VERSION 5.8 ;
BUSBITCHARS "[]" ;
DIVIDERCHAR "/" ;
UNITS
    DATABASE MICRONS 1000 ;
END UNITS

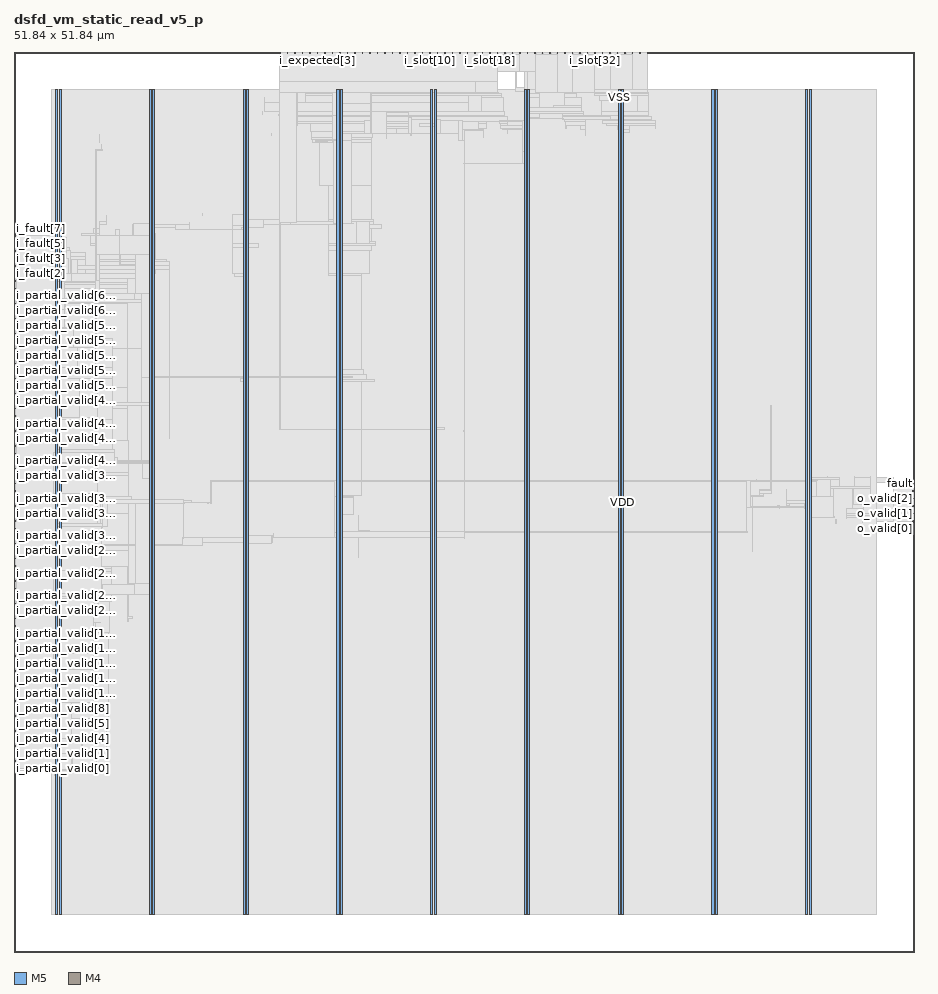
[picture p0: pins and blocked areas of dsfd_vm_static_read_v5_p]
MACRO dsfd_vm_static_read_v5_p
  FOREIGN dsfd_vm_static_read_v5_p 0 0 ;
  CLASS BLOCK ;
  SIZE 51.84 BY 51.84 ;
  PIN ck
    DIRECTION INPUT ;
    USE SIGNAL ;
    PORT
      LAYER M5 ;
        RECT  15.312 51.756 15.336 51.84 ;
    END
  END ck
  PIN fault
    DIRECTION OUTPUT ;
    USE SIGNAL ;
    PORT
      LAYER M4 ;
        RECT  51.756 26.976 51.84 27 ;
    END
  END fault
  PIN i_expected[0]
    DIRECTION INPUT ;
    USE SIGNAL ;
    PORT
      LAYER M5 ;
        RECT  16.176 51.756 16.2 51.84 ;
    END
  END i_expected[0]
  PIN i_expected[1]
    DIRECTION INPUT ;
    USE SIGNAL ;
    PORT
      LAYER M5 ;
        RECT  16.608 51.756 16.632 51.84 ;
    END
  END i_expected[1]
  PIN i_expected[2]
    DIRECTION INPUT ;
    USE SIGNAL ;
    PORT
      LAYER M5 ;
        RECT  17.04 51.756 17.064 51.84 ;
    END
  END i_expected[2]
  PIN i_expected[3]
    DIRECTION INPUT ;
    USE SIGNAL ;
    PORT
      LAYER M5 ;
        RECT  17.472 51.756 17.496 51.84 ;
    END
  END i_expected[3]
  PIN i_expected[4]
    DIRECTION INPUT ;
    USE SIGNAL ;
    PORT
      LAYER M5 ;
        RECT  17.904 51.756 17.928 51.84 ;
    END
  END i_expected[4]
  PIN i_expected[5]
    DIRECTION INPUT ;
    USE SIGNAL ;
    PORT
      LAYER M5 ;
        RECT  18.336 51.756 18.36 51.84 ;
    END
  END i_expected[5]
  PIN i_expected[6]
    DIRECTION INPUT ;
    USE SIGNAL ;
    PORT
      LAYER M5 ;
        RECT  18.768 51.756 18.792 51.84 ;
    END
  END i_expected[6]
  PIN i_expected[7]
    DIRECTION INPUT ;
    USE SIGNAL ;
    PORT
      LAYER M5 ;
        RECT  19.2 51.756 19.224 51.84 ;
    END
  END i_expected[7]
  PIN i_fault[0]
    DIRECTION INPUT ;
    USE SIGNAL ;
    PORT
      LAYER M4 ;
        RECT  0 38.208 0.084 38.232 ;
    END
  END i_fault[0]
  PIN i_fault[1]
    DIRECTION INPUT ;
    USE SIGNAL ;
    PORT
      LAYER M4 ;
        RECT  0 38.64 0.084 38.664 ;
    END
  END i_fault[1]
  PIN i_fault[2]
    DIRECTION INPUT ;
    USE SIGNAL ;
    PORT
      LAYER M4 ;
        RECT  0 39.072 0.084 39.096 ;
    END
  END i_fault[2]
  PIN i_fault[3]
    DIRECTION INPUT ;
    USE SIGNAL ;
    PORT
      LAYER M4 ;
        RECT  0 39.504 0.084 39.528 ;
    END
  END i_fault[3]
  PIN i_fault[4]
    DIRECTION INPUT ;
    USE SIGNAL ;
    PORT
      LAYER M4 ;
        RECT  0 39.936 0.084 39.96 ;
    END
  END i_fault[4]
  PIN i_fault[5]
    DIRECTION INPUT ;
    USE SIGNAL ;
    PORT
      LAYER M4 ;
        RECT  0 40.368 0.084 40.392 ;
    END
  END i_fault[5]
  PIN i_fault[6]
    DIRECTION INPUT ;
    USE SIGNAL ;
    PORT
      LAYER M4 ;
        RECT  0 40.8 0.084 40.824 ;
    END
  END i_fault[6]
  PIN i_fault[7]
    DIRECTION INPUT ;
    USE SIGNAL ;
    PORT
      LAYER M4 ;
        RECT  0 41.232 0.084 41.256 ;
    END
  END i_fault[7]
  PIN i_partial_valid[0]
    DIRECTION INPUT ;
    USE SIGNAL ;
    PORT
      LAYER M4 ;
        RECT  0 10.56 0.084 10.584 ;
    END
  END i_partial_valid[0]
  PIN i_partial_valid[10]
    DIRECTION INPUT ;
    USE SIGNAL ;
    PORT
      LAYER M4 ;
        RECT  0 14.88 0.084 14.904 ;
    END
  END i_partial_valid[10]
  PIN i_partial_valid[11]
    DIRECTION INPUT ;
    USE SIGNAL ;
    PORT
      LAYER M4 ;
        RECT  0 15.312 0.084 15.336 ;
    END
  END i_partial_valid[11]
  PIN i_partial_valid[12]
    DIRECTION INPUT ;
    USE SIGNAL ;
    PORT
      LAYER M4 ;
        RECT  0 15.744 0.084 15.768 ;
    END
  END i_partial_valid[12]
  PIN i_partial_valid[13]
    DIRECTION INPUT ;
    USE SIGNAL ;
    PORT
      LAYER M4 ;
        RECT  0 16.176 0.084 16.2 ;
    END
  END i_partial_valid[13]
  PIN i_partial_valid[14]
    DIRECTION INPUT ;
    USE SIGNAL ;
    PORT
      LAYER M4 ;
        RECT  0 16.608 0.084 16.632 ;
    END
  END i_partial_valid[14]
  PIN i_partial_valid[15]
    DIRECTION INPUT ;
    USE SIGNAL ;
    PORT
      LAYER M4 ;
        RECT  0 17.04 0.084 17.064 ;
    END
  END i_partial_valid[15]
  PIN i_partial_valid[16]
    DIRECTION INPUT ;
    USE SIGNAL ;
    PORT
      LAYER M4 ;
        RECT  0 17.472 0.084 17.496 ;
    END
  END i_partial_valid[16]
  PIN i_partial_valid[17]
    DIRECTION INPUT ;
    USE SIGNAL ;
    PORT
      LAYER M4 ;
        RECT  0 17.904 0.084 17.928 ;
    END
  END i_partial_valid[17]
  PIN i_partial_valid[18]
    DIRECTION INPUT ;
    USE SIGNAL ;
    PORT
      LAYER M4 ;
        RECT  0 18.336 0.084 18.36 ;
    END
  END i_partial_valid[18]
  PIN i_partial_valid[19]
    DIRECTION INPUT ;
    USE SIGNAL ;
    PORT
      LAYER M4 ;
        RECT  0 18.768 0.084 18.792 ;
    END
  END i_partial_valid[19]
  PIN i_partial_valid[1]
    DIRECTION INPUT ;
    USE SIGNAL ;
    PORT
      LAYER M4 ;
        RECT  0 10.992 0.084 11.016 ;
    END
  END i_partial_valid[1]
  PIN i_partial_valid[20]
    DIRECTION INPUT ;
    USE SIGNAL ;
    PORT
      LAYER M4 ;
        RECT  0 19.2 0.084 19.224 ;
    END
  END i_partial_valid[20]
  PIN i_partial_valid[21]
    DIRECTION INPUT ;
    USE SIGNAL ;
    PORT
      LAYER M4 ;
        RECT  0 19.632 0.084 19.656 ;
    END
  END i_partial_valid[21]
  PIN i_partial_valid[22]
    DIRECTION INPUT ;
    USE SIGNAL ;
    PORT
      LAYER M4 ;
        RECT  0 20.064 0.084 20.088 ;
    END
  END i_partial_valid[22]
  PIN i_partial_valid[23]
    DIRECTION INPUT ;
    USE SIGNAL ;
    PORT
      LAYER M4 ;
        RECT  0 20.496 0.084 20.52 ;
    END
  END i_partial_valid[23]
  PIN i_partial_valid[24]
    DIRECTION INPUT ;
    USE SIGNAL ;
    PORT
      LAYER M4 ;
        RECT  0 20.928 0.084 20.952 ;
    END
  END i_partial_valid[24]
  PIN i_partial_valid[25]
    DIRECTION INPUT ;
    USE SIGNAL ;
    PORT
      LAYER M4 ;
        RECT  0 21.36 0.084 21.384 ;
    END
  END i_partial_valid[25]
  PIN i_partial_valid[26]
    DIRECTION INPUT ;
    USE SIGNAL ;
    PORT
      LAYER M4 ;
        RECT  0 21.792 0.084 21.816 ;
    END
  END i_partial_valid[26]
  PIN i_partial_valid[27]
    DIRECTION INPUT ;
    USE SIGNAL ;
    PORT
      LAYER M4 ;
        RECT  0 22.224 0.084 22.248 ;
    END
  END i_partial_valid[27]
  PIN i_partial_valid[28]
    DIRECTION INPUT ;
    USE SIGNAL ;
    PORT
      LAYER M4 ;
        RECT  0 22.656 0.084 22.68 ;
    END
  END i_partial_valid[28]
  PIN i_partial_valid[29]
    DIRECTION INPUT ;
    USE SIGNAL ;
    PORT
      LAYER M4 ;
        RECT  0 23.088 0.084 23.112 ;
    END
  END i_partial_valid[29]
  PIN i_partial_valid[2]
    DIRECTION INPUT ;
    USE SIGNAL ;
    PORT
      LAYER M4 ;
        RECT  0 11.424 0.084 11.448 ;
    END
  END i_partial_valid[2]
  PIN i_partial_valid[30]
    DIRECTION INPUT ;
    USE SIGNAL ;
    PORT
      LAYER M4 ;
        RECT  0 23.52 0.084 23.544 ;
    END
  END i_partial_valid[30]
  PIN i_partial_valid[31]
    DIRECTION INPUT ;
    USE SIGNAL ;
    PORT
      LAYER M4 ;
        RECT  0 23.952 0.084 23.976 ;
    END
  END i_partial_valid[31]
  PIN i_partial_valid[32]
    DIRECTION INPUT ;
    USE SIGNAL ;
    PORT
      LAYER M4 ;
        RECT  0 24.384 0.084 24.408 ;
    END
  END i_partial_valid[32]
  PIN i_partial_valid[33]
    DIRECTION INPUT ;
    USE SIGNAL ;
    PORT
      LAYER M4 ;
        RECT  0 24.816 0.084 24.84 ;
    END
  END i_partial_valid[33]
  PIN i_partial_valid[34]
    DIRECTION INPUT ;
    USE SIGNAL ;
    PORT
      LAYER M4 ;
        RECT  0 25.248 0.084 25.272 ;
    END
  END i_partial_valid[34]
  PIN i_partial_valid[35]
    DIRECTION INPUT ;
    USE SIGNAL ;
    PORT
      LAYER M4 ;
        RECT  0 25.68 0.084 25.704 ;
    END
  END i_partial_valid[35]
  PIN i_partial_valid[36]
    DIRECTION INPUT ;
    USE SIGNAL ;
    PORT
      LAYER M4 ;
        RECT  0 26.112 0.084 26.136 ;
    END
  END i_partial_valid[36]
  PIN i_partial_valid[37]
    DIRECTION INPUT ;
    USE SIGNAL ;
    PORT
      LAYER M4 ;
        RECT  0 26.544 0.084 26.568 ;
    END
  END i_partial_valid[37]
  PIN i_partial_valid[38]
    DIRECTION INPUT ;
    USE SIGNAL ;
    PORT
      LAYER M4 ;
        RECT  0 26.976 0.084 27 ;
    END
  END i_partial_valid[38]
  PIN i_partial_valid[39]
    DIRECTION INPUT ;
    USE SIGNAL ;
    PORT
      LAYER M4 ;
        RECT  0 27.408 0.084 27.432 ;
    END
  END i_partial_valid[39]
  PIN i_partial_valid[3]
    DIRECTION INPUT ;
    USE SIGNAL ;
    PORT
      LAYER M4 ;
        RECT  0 11.856 0.084 11.88 ;
    END
  END i_partial_valid[3]
  PIN i_partial_valid[40]
    DIRECTION INPUT ;
    USE SIGNAL ;
    PORT
      LAYER M4 ;
        RECT  0 27.84 0.084 27.864 ;
    END
  END i_partial_valid[40]
  PIN i_partial_valid[41]
    DIRECTION INPUT ;
    USE SIGNAL ;
    PORT
      LAYER M4 ;
        RECT  0 28.272 0.084 28.296 ;
    END
  END i_partial_valid[41]
  PIN i_partial_valid[42]
    DIRECTION INPUT ;
    USE SIGNAL ;
    PORT
      LAYER M4 ;
        RECT  0 28.704 0.084 28.728 ;
    END
  END i_partial_valid[42]
  PIN i_partial_valid[43]
    DIRECTION INPUT ;
    USE SIGNAL ;
    PORT
      LAYER M4 ;
        RECT  0 29.136 0.084 29.16 ;
    END
  END i_partial_valid[43]
  PIN i_partial_valid[44]
    DIRECTION INPUT ;
    USE SIGNAL ;
    PORT
      LAYER M4 ;
        RECT  0 29.568 0.084 29.592 ;
    END
  END i_partial_valid[44]
  PIN i_partial_valid[45]
    DIRECTION INPUT ;
    USE SIGNAL ;
    PORT
      LAYER M4 ;
        RECT  0 30 0.084 30.024 ;
    END
  END i_partial_valid[45]
  PIN i_partial_valid[46]
    DIRECTION INPUT ;
    USE SIGNAL ;
    PORT
      LAYER M4 ;
        RECT  0 30.432 0.084 30.456 ;
    END
  END i_partial_valid[46]
  PIN i_partial_valid[47]
    DIRECTION INPUT ;
    USE SIGNAL ;
    PORT
      LAYER M4 ;
        RECT  0 30.864 0.084 30.888 ;
    END
  END i_partial_valid[47]
  PIN i_partial_valid[48]
    DIRECTION INPUT ;
    USE SIGNAL ;
    PORT
      LAYER M4 ;
        RECT  0 31.296 0.084 31.32 ;
    END
  END i_partial_valid[48]
  PIN i_partial_valid[49]
    DIRECTION INPUT ;
    USE SIGNAL ;
    PORT
      LAYER M4 ;
        RECT  0 31.728 0.084 31.752 ;
    END
  END i_partial_valid[49]
  PIN i_partial_valid[4]
    DIRECTION INPUT ;
    USE SIGNAL ;
    PORT
      LAYER M4 ;
        RECT  0 12.288 0.084 12.312 ;
    END
  END i_partial_valid[4]
  PIN i_partial_valid[50]
    DIRECTION INPUT ;
    USE SIGNAL ;
    PORT
      LAYER M4 ;
        RECT  0 32.16 0.084 32.184 ;
    END
  END i_partial_valid[50]
  PIN i_partial_valid[51]
    DIRECTION INPUT ;
    USE SIGNAL ;
    PORT
      LAYER M4 ;
        RECT  0 32.592 0.084 32.616 ;
    END
  END i_partial_valid[51]
  PIN i_partial_valid[52]
    DIRECTION INPUT ;
    USE SIGNAL ;
    PORT
      LAYER M4 ;
        RECT  0 33.024 0.084 33.048 ;
    END
  END i_partial_valid[52]
  PIN i_partial_valid[53]
    DIRECTION INPUT ;
    USE SIGNAL ;
    PORT
      LAYER M4 ;
        RECT  0 33.456 0.084 33.48 ;
    END
  END i_partial_valid[53]
  PIN i_partial_valid[54]
    DIRECTION INPUT ;
    USE SIGNAL ;
    PORT
      LAYER M4 ;
        RECT  0 33.888 0.084 33.912 ;
    END
  END i_partial_valid[54]
  PIN i_partial_valid[55]
    DIRECTION INPUT ;
    USE SIGNAL ;
    PORT
      LAYER M4 ;
        RECT  0 34.32 0.084 34.344 ;
    END
  END i_partial_valid[55]
  PIN i_partial_valid[56]
    DIRECTION INPUT ;
    USE SIGNAL ;
    PORT
      LAYER M4 ;
        RECT  0 34.752 0.084 34.776 ;
    END
  END i_partial_valid[56]
  PIN i_partial_valid[57]
    DIRECTION INPUT ;
    USE SIGNAL ;
    PORT
      LAYER M4 ;
        RECT  0 35.184 0.084 35.208 ;
    END
  END i_partial_valid[57]
  PIN i_partial_valid[58]
    DIRECTION INPUT ;
    USE SIGNAL ;
    PORT
      LAYER M4 ;
        RECT  0 35.616 0.084 35.64 ;
    END
  END i_partial_valid[58]
  PIN i_partial_valid[59]
    DIRECTION INPUT ;
    USE SIGNAL ;
    PORT
      LAYER M4 ;
        RECT  0 36.048 0.084 36.072 ;
    END
  END i_partial_valid[59]
  PIN i_partial_valid[5]
    DIRECTION INPUT ;
    USE SIGNAL ;
    PORT
      LAYER M4 ;
        RECT  0 12.72 0.084 12.744 ;
    END
  END i_partial_valid[5]
  PIN i_partial_valid[60]
    DIRECTION INPUT ;
    USE SIGNAL ;
    PORT
      LAYER M4 ;
        RECT  0 36.48 0.084 36.504 ;
    END
  END i_partial_valid[60]
  PIN i_partial_valid[61]
    DIRECTION INPUT ;
    USE SIGNAL ;
    PORT
      LAYER M4 ;
        RECT  0 36.912 0.084 36.936 ;
    END
  END i_partial_valid[61]
  PIN i_partial_valid[62]
    DIRECTION INPUT ;
    USE SIGNAL ;
    PORT
      LAYER M4 ;
        RECT  0 37.344 0.084 37.368 ;
    END
  END i_partial_valid[62]
  PIN i_partial_valid[63]
    DIRECTION INPUT ;
    USE SIGNAL ;
    PORT
      LAYER M4 ;
        RECT  0 37.776 0.084 37.8 ;
    END
  END i_partial_valid[63]
  PIN i_partial_valid[6]
    DIRECTION INPUT ;
    USE SIGNAL ;
    PORT
      LAYER M4 ;
        RECT  0 13.152 0.084 13.176 ;
    END
  END i_partial_valid[6]
  PIN i_partial_valid[7]
    DIRECTION INPUT ;
    USE SIGNAL ;
    PORT
      LAYER M4 ;
        RECT  0 13.584 0.084 13.608 ;
    END
  END i_partial_valid[7]
  PIN i_partial_valid[8]
    DIRECTION INPUT ;
    USE SIGNAL ;
    PORT
      LAYER M4 ;
        RECT  0 14.016 0.084 14.04 ;
    END
  END i_partial_valid[8]
  PIN i_partial_valid[9]
    DIRECTION INPUT ;
    USE SIGNAL ;
    PORT
      LAYER M4 ;
        RECT  0 14.448 0.084 14.472 ;
    END
  END i_partial_valid[9]
  PIN i_slot[0]
    DIRECTION INPUT ;
    USE SIGNAL ;
    PORT
      LAYER M5 ;
        RECT  19.632 51.756 19.656 51.84 ;
    END
  END i_slot[0]
  PIN i_slot[10]
    DIRECTION INPUT ;
    USE SIGNAL ;
    PORT
      LAYER M5 ;
        RECT  23.952 51.756 23.976 51.84 ;
    END
  END i_slot[10]
  PIN i_slot[11]
    DIRECTION INPUT ;
    USE SIGNAL ;
    PORT
      LAYER M5 ;
        RECT  24.384 51.756 24.408 51.84 ;
    END
  END i_slot[11]
  PIN i_slot[12]
    DIRECTION INPUT ;
    USE SIGNAL ;
    PORT
      LAYER M5 ;
        RECT  24.816 51.756 24.84 51.84 ;
    END
  END i_slot[12]
  PIN i_slot[13]
    DIRECTION INPUT ;
    USE SIGNAL ;
    PORT
      LAYER M5 ;
        RECT  25.248 51.756 25.272 51.84 ;
    END
  END i_slot[13]
  PIN i_slot[14]
    DIRECTION INPUT ;
    USE SIGNAL ;
    PORT
      LAYER M5 ;
        RECT  25.68 51.756 25.704 51.84 ;
    END
  END i_slot[14]
  PIN i_slot[15]
    DIRECTION INPUT ;
    USE SIGNAL ;
    PORT
      LAYER M5 ;
        RECT  26.112 51.756 26.136 51.84 ;
    END
  END i_slot[15]
  PIN i_slot[16]
    DIRECTION INPUT ;
    USE SIGNAL ;
    PORT
      LAYER M5 ;
        RECT  26.544 51.756 26.568 51.84 ;
    END
  END i_slot[16]
  PIN i_slot[17]
    DIRECTION INPUT ;
    USE SIGNAL ;
    PORT
      LAYER M5 ;
        RECT  26.976 51.756 27 51.84 ;
    END
  END i_slot[17]
  PIN i_slot[18]
    DIRECTION INPUT ;
    USE SIGNAL ;
    PORT
      LAYER M5 ;
        RECT  27.408 51.756 27.432 51.84 ;
    END
  END i_slot[18]
  PIN i_slot[19]
    DIRECTION INPUT ;
    USE SIGNAL ;
    PORT
      LAYER M5 ;
        RECT  27.84 51.756 27.864 51.84 ;
    END
  END i_slot[19]
  PIN i_slot[1]
    DIRECTION INPUT ;
    USE SIGNAL ;
    PORT
      LAYER M5 ;
        RECT  20.064 51.756 20.088 51.84 ;
    END
  END i_slot[1]
  PIN i_slot[20]
    DIRECTION INPUT ;
    USE SIGNAL ;
    PORT
      LAYER M5 ;
        RECT  28.272 51.756 28.296 51.84 ;
    END
  END i_slot[20]
  PIN i_slot[21]
    DIRECTION INPUT ;
    USE SIGNAL ;
    PORT
      LAYER M5 ;
        RECT  28.704 51.756 28.728 51.84 ;
    END
  END i_slot[21]
  PIN i_slot[22]
    DIRECTION INPUT ;
    USE SIGNAL ;
    PORT
      LAYER M5 ;
        RECT  29.136 51.756 29.16 51.84 ;
    END
  END i_slot[22]
  PIN i_slot[23]
    DIRECTION INPUT ;
    USE SIGNAL ;
    PORT
      LAYER M5 ;
        RECT  29.568 51.756 29.592 51.84 ;
    END
  END i_slot[23]
  PIN i_slot[24]
    DIRECTION INPUT ;
    USE SIGNAL ;
    PORT
      LAYER M5 ;
        RECT  30 51.756 30.024 51.84 ;
    END
  END i_slot[24]
  PIN i_slot[25]
    DIRECTION INPUT ;
    USE SIGNAL ;
    PORT
      LAYER M5 ;
        RECT  30.432 51.756 30.456 51.84 ;
    END
  END i_slot[25]
  PIN i_slot[26]
    DIRECTION INPUT ;
    USE SIGNAL ;
    PORT
      LAYER M5 ;
        RECT  30.864 51.756 30.888 51.84 ;
    END
  END i_slot[26]
  PIN i_slot[27]
    DIRECTION INPUT ;
    USE SIGNAL ;
    PORT
      LAYER M5 ;
        RECT  31.296 51.756 31.32 51.84 ;
    END
  END i_slot[27]
  PIN i_slot[28]
    DIRECTION INPUT ;
    USE SIGNAL ;
    PORT
      LAYER M5 ;
        RECT  31.728 51.756 31.752 51.84 ;
    END
  END i_slot[28]
  PIN i_slot[29]
    DIRECTION INPUT ;
    USE SIGNAL ;
    PORT
      LAYER M5 ;
        RECT  32.16 51.756 32.184 51.84 ;
    END
  END i_slot[29]
  PIN i_slot[2]
    DIRECTION INPUT ;
    USE SIGNAL ;
    PORT
      LAYER M5 ;
        RECT  20.496 51.756 20.52 51.84 ;
    END
  END i_slot[2]
  PIN i_slot[30]
    DIRECTION INPUT ;
    USE SIGNAL ;
    PORT
      LAYER M5 ;
        RECT  32.592 51.756 32.616 51.84 ;
    END
  END i_slot[30]
  PIN i_slot[31]
    DIRECTION INPUT ;
    USE SIGNAL ;
    PORT
      LAYER M5 ;
        RECT  33.024 51.756 33.048 51.84 ;
    END
  END i_slot[31]
  PIN i_slot[32]
    DIRECTION INPUT ;
    USE SIGNAL ;
    PORT
      LAYER M5 ;
        RECT  33.456 51.756 33.48 51.84 ;
    END
  END i_slot[32]
  PIN i_slot[33]
    DIRECTION INPUT ;
    USE SIGNAL ;
    PORT
      LAYER M5 ;
        RECT  33.888 51.756 33.912 51.84 ;
    END
  END i_slot[33]
  PIN i_slot[34]
    DIRECTION INPUT ;
    USE SIGNAL ;
    PORT
      LAYER M5 ;
        RECT  34.32 51.756 34.344 51.84 ;
    END
  END i_slot[34]
  PIN i_slot[35]
    DIRECTION INPUT ;
    USE SIGNAL ;
    PORT
      LAYER M5 ;
        RECT  34.752 51.756 34.776 51.84 ;
    END
  END i_slot[35]
  PIN i_slot[36]
    DIRECTION INPUT ;
    USE SIGNAL ;
    PORT
      LAYER M5 ;
        RECT  35.184 51.756 35.208 51.84 ;
    END
  END i_slot[36]
  PIN i_slot[37]
    DIRECTION INPUT ;
    USE SIGNAL ;
    PORT
      LAYER M5 ;
        RECT  35.616 51.756 35.64 51.84 ;
    END
  END i_slot[37]
  PIN i_slot[38]
    DIRECTION INPUT ;
    USE SIGNAL ;
    PORT
      LAYER M5 ;
        RECT  36.048 51.756 36.072 51.84 ;
    END
  END i_slot[38]
  PIN i_slot[39]
    DIRECTION INPUT ;
    USE SIGNAL ;
    PORT
      LAYER M5 ;
        RECT  36.48 51.756 36.504 51.84 ;
    END
  END i_slot[39]
  PIN i_slot[3]
    DIRECTION INPUT ;
    USE SIGNAL ;
    PORT
      LAYER M5 ;
        RECT  20.928 51.756 20.952 51.84 ;
    END
  END i_slot[3]
  PIN i_slot[4]
    DIRECTION INPUT ;
    USE SIGNAL ;
    PORT
      LAYER M5 ;
        RECT  21.36 51.756 21.384 51.84 ;
    END
  END i_slot[4]
  PIN i_slot[5]
    DIRECTION INPUT ;
    USE SIGNAL ;
    PORT
      LAYER M5 ;
        RECT  21.792 51.756 21.816 51.84 ;
    END
  END i_slot[5]
  PIN i_slot[6]
    DIRECTION INPUT ;
    USE SIGNAL ;
    PORT
      LAYER M5 ;
        RECT  22.224 51.756 22.248 51.84 ;
    END
  END i_slot[6]
  PIN i_slot[7]
    DIRECTION INPUT ;
    USE SIGNAL ;
    PORT
      LAYER M5 ;
        RECT  22.656 51.756 22.68 51.84 ;
    END
  END i_slot[7]
  PIN i_slot[8]
    DIRECTION INPUT ;
    USE SIGNAL ;
    PORT
      LAYER M5 ;
        RECT  23.088 51.756 23.112 51.84 ;
    END
  END i_slot[8]
  PIN i_slot[9]
    DIRECTION INPUT ;
    USE SIGNAL ;
    PORT
      LAYER M5 ;
        RECT  23.52 51.756 23.544 51.84 ;
    END
  END i_slot[9]
  PIN o_valid[0]
    DIRECTION OUTPUT ;
    USE SIGNAL ;
    PORT
      LAYER M4 ;
        RECT  51.756 24.816 51.84 24.84 ;
    END
  END o_valid[0]
  PIN o_valid[1]
    DIRECTION OUTPUT ;
    USE SIGNAL ;
    PORT
      LAYER M4 ;
        RECT  51.756 25.248 51.84 25.272 ;
    END
  END o_valid[1]
  PIN o_valid[2]
    DIRECTION OUTPUT ;
    USE SIGNAL ;
    PORT
      LAYER M4 ;
        RECT  51.756 25.68 51.84 25.704 ;
    END
  END o_valid[2]
  PIN o_valid[3]
    DIRECTION OUTPUT ;
    USE SIGNAL ;
    PORT
      LAYER M4 ;
        RECT  51.756 26.112 51.84 26.136 ;
    END
  END o_valid[3]
  PIN o_valid[4]
    DIRECTION OUTPUT ;
    USE SIGNAL ;
    PORT
      LAYER M4 ;
        RECT  51.756 26.544 51.84 26.568 ;
    END
  END o_valid[4]
  PIN rst_n
    DIRECTION INPUT ;
    USE SIGNAL ;
    PORT
      LAYER M5 ;
        RECT  15.744 51.756 15.768 51.84 ;
    END
  END rst_n
  PIN VDD
    DIRECTION INOUT ;
    USE POWER ;
    PORT
      LAYER M5 ;
        RECT  45.792 2.151 45.912 49.689 ;
        RECT  40.392 2.151 40.512 49.689 ;
        RECT  34.992 2.151 35.112 49.689 ;
        RECT  29.592 2.151 29.712 49.689 ;
        RECT  24.192 2.151 24.312 49.689 ;
        RECT  18.792 2.151 18.912 49.689 ;
        RECT  13.392 2.151 13.512 49.689 ;
        RECT  7.992 2.151 8.112 49.689 ;
        RECT  2.592 2.151 2.712 49.689 ;
    END
  END VDD
  PIN VSS
    DIRECTION INOUT ;
    USE GROUND ;
    PORT
      LAYER M5 ;
        RECT  45.6 2.137 45.72 49.703 ;
        RECT  40.2 2.137 40.32 49.703 ;
        RECT  34.8 2.137 34.92 49.703 ;
        RECT  29.4 2.137 29.52 49.703 ;
        RECT  24 2.137 24.12 49.703 ;
        RECT  18.6 2.137 18.72 49.703 ;
        RECT  13.2 2.137 13.32 49.703 ;
        RECT  7.8 2.137 7.92 49.703 ;
        RECT  2.4 2.137 2.52 49.703 ;
    END
  END VSS
  # OT_OBS_CLOSED layer=M5 d_um=1.536 added=32
  OBS
    LAYER RVTN ;
     RECT  2.16 2.16 49.68 2.295 ;
     RECT  2.16 2.565 49.68 2.835 ;
     RECT  2.16 3.105 49.68 3.375 ;
     RECT  2.16 3.645 49.68 3.915 ;
     RECT  2.16 4.185 49.68 4.455 ;
     RECT  2.16 4.725 49.68 4.995 ;
     RECT  2.16 5.265 49.68 5.535 ;
     RECT  2.16 5.805 49.68 6.075 ;
     RECT  2.16 6.345 49.68 6.615 ;
     RECT  2.16 6.885 49.68 7.155 ;
     RECT  2.16 7.425 49.68 7.695 ;
     RECT  2.16 7.965 49.68 8.235 ;
     RECT  2.16 8.505 49.68 8.775 ;
     RECT  2.16 9.045 49.68 9.315 ;
     RECT  2.16 9.585 49.68 9.855 ;
     RECT  2.16 10.125 49.68 10.395 ;
     RECT  2.16 10.665 49.68 10.935 ;
     RECT  2.16 11.205 49.68 11.475 ;
     RECT  2.16 11.745 49.68 12.015 ;
     RECT  2.16 12.285 49.68 12.555 ;
     RECT  2.16 12.825 49.68 13.095 ;
     RECT  2.16 13.365 49.68 13.635 ;
     RECT  2.16 13.905 49.68 14.175 ;
     RECT  2.16 14.445 49.68 14.715 ;
     RECT  2.16 14.985 49.68 15.255 ;
     RECT  2.16 15.525 49.68 15.795 ;
     RECT  2.16 16.065 49.68 16.335 ;
     RECT  2.16 16.605 49.68 16.875 ;
     RECT  2.16 17.145 49.68 17.415 ;
     RECT  2.16 17.685 49.68 17.955 ;
     RECT  2.16 18.225 49.68 18.495 ;
     RECT  2.16 18.765 49.68 19.035 ;
     RECT  2.16 19.305 49.68 19.575 ;
     RECT  2.16 19.845 49.68 20.115 ;
     RECT  2.16 20.385 49.68 20.655 ;
     RECT  2.16 20.925 49.68 21.195 ;
     RECT  2.16 21.465 49.68 21.735 ;
     RECT  2.16 22.005 49.68 22.275 ;
     RECT  2.16 22.545 49.68 22.815 ;
     RECT  2.16 23.085 49.68 23.355 ;
     RECT  2.16 23.625 49.68 23.895 ;
     RECT  2.16 24.165 49.68 24.435 ;
     RECT  2.16 24.705 49.68 24.975 ;
     RECT  2.16 25.245 49.68 25.515 ;
     RECT  2.16 25.785 49.68 26.055 ;
     RECT  2.16 26.325 49.68 26.595 ;
     RECT  2.16 26.865 49.68 27.135 ;
     RECT  2.16 27.405 49.68 27.675 ;
     RECT  2.16 27.945 49.68 28.215 ;
     RECT  2.16 28.485 49.68 28.755 ;
     RECT  2.16 29.025 49.68 29.295 ;
     RECT  2.16 29.565 49.68 29.835 ;
     RECT  2.16 30.105 49.68 30.375 ;
     RECT  2.16 30.645 49.68 30.915 ;
     RECT  2.16 31.185 49.68 31.455 ;
     RECT  2.16 31.725 49.68 31.995 ;
     RECT  2.16 32.265 49.68 32.535 ;
     RECT  2.16 32.805 49.68 33.075 ;
     RECT  2.16 33.345 49.68 33.615 ;
     RECT  2.16 33.885 49.68 34.155 ;
     RECT  2.16 34.425 49.68 34.695 ;
     RECT  2.16 34.965 49.68 35.235 ;
     RECT  2.16 35.505 49.68 35.775 ;
     RECT  2.16 36.045 49.68 36.315 ;
     RECT  2.16 36.585 49.68 36.855 ;
     RECT  2.16 37.125 49.68 37.395 ;
     RECT  2.16 37.665 49.68 37.935 ;
     RECT  2.16 38.205 49.68 38.475 ;
     RECT  2.16 38.745 49.68 39.015 ;
     RECT  2.16 39.285 49.68 39.555 ;
     RECT  2.16 39.825 49.68 40.095 ;
     RECT  2.16 40.365 49.68 40.635 ;
     RECT  2.16 40.905 49.68 41.175 ;
     RECT  2.16 41.445 49.68 41.715 ;
     RECT  2.16 41.985 49.68 42.255 ;
     RECT  2.16 42.525 49.68 42.795 ;
     RECT  2.16 43.065 49.68 43.335 ;
     RECT  2.16 43.605 49.68 43.875 ;
     RECT  2.16 44.145 49.68 44.415 ;
     RECT  2.16 44.685 49.68 44.955 ;
     RECT  2.16 45.225 49.68 45.495 ;
     RECT  2.16 45.765 49.68 46.035 ;
     RECT  2.16 46.305 49.68 46.575 ;
     RECT  2.16 46.845 49.68 47.115 ;
     RECT  2.16 47.385 49.68 47.655 ;
     RECT  2.16 47.925 49.68 48.195 ;
     RECT  2.16 48.465 49.68 48.735 ;
     RECT  2.16 49.005 49.68 49.275 ;
     RECT  2.16 49.545 49.68 49.68 ;
    LAYER RVTP ;
     RECT  2.16 2.295 49.68 2.565 ;
     RECT  2.16 2.835 49.68 3.105 ;
     RECT  2.16 3.375 49.68 3.645 ;
     RECT  2.16 3.915 49.68 4.185 ;
     RECT  2.16 4.455 49.68 4.725 ;
     RECT  2.16 4.995 49.68 5.265 ;
     RECT  2.16 5.535 49.68 5.805 ;
     RECT  2.16 6.075 49.68 6.345 ;
     RECT  2.16 6.615 49.68 6.885 ;
     RECT  2.16 7.155 49.68 7.425 ;
     RECT  2.16 7.695 49.68 7.965 ;
     RECT  2.16 8.235 49.68 8.505 ;
     RECT  2.16 8.775 49.68 9.045 ;
     RECT  2.16 9.315 49.68 9.585 ;
     RECT  2.16 9.855 49.68 10.125 ;
     RECT  2.16 10.395 49.68 10.665 ;
     RECT  2.16 10.935 49.68 11.205 ;
     RECT  2.16 11.475 49.68 11.745 ;
     RECT  2.16 12.015 49.68 12.285 ;
     RECT  2.16 12.555 49.68 12.825 ;
     RECT  2.16 13.095 49.68 13.365 ;
     RECT  2.16 13.635 49.68 13.905 ;
     RECT  2.16 14.175 49.68 14.445 ;
     RECT  2.16 14.715 49.68 14.985 ;
     RECT  2.16 15.255 49.68 15.525 ;
     RECT  2.16 15.795 49.68 16.065 ;
     RECT  2.16 16.335 49.68 16.605 ;
     RECT  2.16 16.875 49.68 17.145 ;
     RECT  2.16 17.415 49.68 17.685 ;
     RECT  2.16 17.955 49.68 18.225 ;
     RECT  2.16 18.495 49.68 18.765 ;
     RECT  2.16 19.035 49.68 19.305 ;
     RECT  2.16 19.575 49.68 19.845 ;
     RECT  2.16 20.115 49.68 20.385 ;
     RECT  2.16 20.655 49.68 20.925 ;
     RECT  2.16 21.195 49.68 21.465 ;
     RECT  2.16 21.735 49.68 22.005 ;
     RECT  2.16 22.275 49.68 22.545 ;
     RECT  2.16 22.815 49.68 23.085 ;
     RECT  2.16 23.355 49.68 23.625 ;
     RECT  2.16 23.895 49.68 24.165 ;
     RECT  2.16 24.435 49.68 24.705 ;
     RECT  2.16 24.975 49.68 25.245 ;
     RECT  2.16 25.515 49.68 25.785 ;
     RECT  2.16 26.055 49.68 26.325 ;
     RECT  2.16 26.595 49.68 26.865 ;
     RECT  2.16 27.135 49.68 27.405 ;
     RECT  2.16 27.675 49.68 27.945 ;
     RECT  2.16 28.215 49.68 28.485 ;
     RECT  2.16 28.755 49.68 29.025 ;
     RECT  2.16 29.295 49.68 29.565 ;
     RECT  2.16 29.835 49.68 30.105 ;
     RECT  2.16 30.375 49.68 30.645 ;
     RECT  2.16 30.915 49.68 31.185 ;
     RECT  2.16 31.455 49.68 31.725 ;
     RECT  2.16 31.995 49.68 32.265 ;
     RECT  2.16 32.535 49.68 32.805 ;
     RECT  2.16 33.075 49.68 33.345 ;
     RECT  2.16 33.615 49.68 33.885 ;
     RECT  2.16 34.155 49.68 34.425 ;
     RECT  2.16 34.695 49.68 34.965 ;
     RECT  2.16 35.235 49.68 35.505 ;
     RECT  2.16 35.775 49.68 36.045 ;
     RECT  2.16 36.315 49.68 36.585 ;
     RECT  2.16 36.855 49.68 37.125 ;
     RECT  2.16 37.395 49.68 37.665 ;
     RECT  2.16 37.935 49.68 38.205 ;
     RECT  2.16 38.475 49.68 38.745 ;
     RECT  2.16 39.015 49.68 39.285 ;
     RECT  2.16 39.555 49.68 39.825 ;
     RECT  2.16 40.095 49.68 40.365 ;
     RECT  2.16 40.635 49.68 40.905 ;
     RECT  2.16 41.175 49.68 41.445 ;
     RECT  2.16 41.715 49.68 41.985 ;
     RECT  2.16 42.255 49.68 42.525 ;
     RECT  2.16 42.795 49.68 43.065 ;
     RECT  2.16 43.335 49.68 43.605 ;
     RECT  2.16 43.875 49.68 44.145 ;
     RECT  2.16 44.415 49.68 44.685 ;
     RECT  2.16 44.955 49.68 45.225 ;
     RECT  2.16 45.495 49.68 45.765 ;
     RECT  2.16 46.035 49.68 46.305 ;
     RECT  2.16 46.575 49.68 46.845 ;
     RECT  2.16 47.115 49.68 47.385 ;
     RECT  2.16 47.655 49.68 47.925 ;
     RECT  2.16 48.195 49.68 48.465 ;
     RECT  2.16 48.735 49.68 49.005 ;
     RECT  2.16 49.275 49.68 49.545 ;
    LAYER M1 ;
     RECT  2.16 2.151 49.68 49.689 ;
    LAYER M2 ;
     RECT  0.103 32.346 1.723 32.364 ;
     RECT  0.103 10.44 2.16 10.458 ;
     RECT  0.103 13.95 2.16 13.968 ;
     RECT  2.155 21.906 2.16 21.924 ;
     RECT  2.155 23.094 2.16 23.112 ;
     RECT  0.103 25.326 2.16 25.344 ;
     RECT  1.723 32.346 2.16 32.49 ;
     RECT  2.16 2.151 49.68 49.689 ;
     RECT  49.68 27.036 50.675 27.324 ;
     RECT  49.68 24.786 50.711 26.118 ;
     RECT  50.675 27.036 50.711 27.054 ;
    LAYER M3 ;
     RECT  2.415 2.143 2.505 2.413 ;
     RECT  7.815 2.143 7.905 2.413 ;
     RECT  13.215 2.143 13.305 2.413 ;
     RECT  18.615 2.143 18.705 2.413 ;
     RECT  24.015 2.143 24.105 2.413 ;
     RECT  29.415 2.143 29.505 2.413 ;
     RECT  34.815 2.143 34.905 2.413 ;
     RECT  40.215 2.143 40.305 2.413 ;
     RECT  45.615 2.143 45.705 2.413 ;
     RECT  2.415 2.413 2.697 10.165 ;
     RECT  2.34 10.165 2.697 10.201 ;
     RECT  4.068 10.399 4.086 10.435 ;
     RECT  2.34 10.201 2.754 10.471 ;
     RECT  3.924 10.435 4.086 10.471 ;
     RECT  2.34 10.471 4.734 10.555 ;
     RECT  2.304 10.555 4.734 10.625 ;
     RECT  0.108 10.435 0.126 11.021 ;
     RECT  2.34 10.625 4.734 11.281 ;
     RECT  0.108 11.851 0.126 11.981 ;
     RECT  2.34 11.281 5.346 12.091 ;
     RECT  2.304 12.091 5.346 13.441 ;
     RECT  0.108 13.945 0.126 14.909 ;
     RECT  2.304 13.441 5.454 18.265 ;
     RECT  2.232 18.265 5.454 18.427 ;
     RECT  6.552 19.039 6.57 19.237 ;
     RECT  6.552 19.237 6.822 19.337 ;
     RECT  2.232 18.427 5.49 19.381 ;
     RECT  2.232 19.381 5.526 20.191 ;
     RECT  6.552 19.337 6.57 20.587 ;
     RECT  6.552 20.587 6.93 20.695 ;
     RECT  6.552 20.695 7.002 20.731 ;
     RECT  7.815 2.413 8.097 20.731 ;
     RECT  6.552 20.731 8.097 21.149 ;
     RECT  6.552 21.149 7.002 21.245 ;
     RECT  2.232 20.191 5.598 21.901 ;
     RECT  2.16 21.901 5.598 22.081 ;
     RECT  2.16 22.081 5.634 22.207 ;
     RECT  6.552 21.245 6.57 22.207 ;
     RECT  2.16 22.207 6.57 23.117 ;
     RECT  10.836 23.419 10.854 23.597 ;
     RECT  19.836 22.747 19.854 23.851 ;
     RECT  19.836 23.851 20.358 23.971 ;
     RECT  14.94 23.851 14.958 24.089 ;
     RECT  19.836 23.971 20.502 24.269 ;
     RECT  47.34 24.709 47.358 24.899 ;
     RECT  47.952 24.979 47.97 25.015 ;
     RECT  47.952 25.015 48.042 25.051 ;
     RECT  48.852 24.745 48.87 25.051 ;
     RECT  47.196 25.045 47.214 25.085 ;
     RECT  47.952 25.051 48.87 25.141 ;
     RECT  18.615 2.413 18.897 25.147 ;
     RECT  19.836 24.269 19.854 25.169 ;
     RECT  18.54 25.147 18.897 25.177 ;
     RECT  18.54 25.177 19.53 25.205 ;
     RECT  47.952 25.141 49.338 25.241 ;
     RECT  2.196 23.117 6.57 25.277 ;
     RECT  45.615 2.413 45.897 25.519 ;
     RECT  45.615 25.519 46.998 25.531 ;
     RECT  47.952 25.241 48.942 25.547 ;
     RECT  44.1 25.519 44.118 25.627 ;
     RECT  0.108 25.321 0.126 25.709 ;
     RECT  43.956 25.627 44.118 25.709 ;
     RECT  45.54 25.531 46.998 25.781 ;
     RECT  48.312 25.547 48.942 25.781 ;
     RECT  9.72 25.819 9.738 25.859 ;
     RECT  44.496 25.717 44.694 25.861 ;
     RECT  45.54 25.781 46.206 25.861 ;
     RECT  11.16 25.861 11.178 25.901 ;
     RECT  2.232 25.277 6.57 25.951 ;
     RECT  9.756 25.867 10.242 25.979 ;
     RECT  44.496 25.861 46.206 26.015 ;
     RECT  9.756 25.979 9.774 26.045 ;
     RECT  50.688 24.781 50.706 26.141 ;
     RECT  18.615 25.205 19.53 26.203 ;
     RECT  2.232 25.951 6.75 26.249 ;
     RECT  18.576 26.203 19.53 26.249 ;
     RECT  42.516 23.089 42.534 26.251 ;
     RECT  42.372 26.251 42.534 26.257 ;
     RECT  42.372 26.257 43.182 26.291 ;
     RECT  18.615 26.249 19.53 26.293 ;
     RECT  42.912 26.291 43.182 26.401 ;
     RECT  42.912 26.401 43.65 26.555 ;
     RECT  42.912 26.555 43.614 26.627 ;
     RECT  44.496 26.015 44.514 26.627 ;
     RECT  47.052 26.203 47.214 26.671 ;
     RECT  48.312 25.781 48.33 26.671 ;
     RECT  49.32 26.095 49.338 26.671 ;
     RECT  47.052 26.671 49.338 26.825 ;
     RECT  50.652 26.539 50.67 26.971 ;
     RECT  50.652 26.971 50.706 27.059 ;
     RECT  45.615 26.015 46.206 27.103 ;
     RECT  1.152 26.971 1.17 27.149 ;
     RECT  45.54 27.103 46.206 27.149 ;
     RECT  45.615 27.149 46.206 27.175 ;
     RECT  45.615 27.175 46.278 27.211 ;
     RECT  47.052 26.825 47.574 27.211 ;
     RECT  42.768 27.139 42.786 27.239 ;
     RECT  7.815 21.149 8.097 27.301 ;
     RECT  45.615 27.211 47.574 27.329 ;
     RECT  48.384 26.825 49.338 27.329 ;
     RECT  50.652 27.059 50.67 27.329 ;
     RECT  46.836 27.329 46.854 27.365 ;
     RECT  48.384 27.329 48.402 27.365 ;
     RECT  49.32 27.329 49.338 27.365 ;
     RECT  2.232 26.249 6.57 27.445 ;
     RECT  2.196 27.445 6.57 27.599 ;
     RECT  2.232 27.599 6.57 28.111 ;
     RECT  7.416 27.301 8.097 28.111 ;
     RECT  2.232 28.111 8.097 28.283 ;
     RECT  2.232 28.283 6.57 29.489 ;
     RECT  25.92 29.995 25.938 30.035 ;
     RECT  24.015 2.413 24.297 30.091 ;
     RECT  24.015 30.091 24.786 30.209 ;
     RECT  2.232 29.489 6.534 31.291 ;
     RECT  1.728 31.291 6.534 31.459 ;
     RECT  7.344 28.283 8.097 31.459 ;
     RECT  43.596 26.627 43.614 31.487 ;
     RECT  1.728 31.459 8.097 31.649 ;
     RECT  1.728 31.649 6.534 32.495 ;
     RECT  0.108 32.341 0.126 32.621 ;
     RECT  13.215 2.413 13.497 32.881 ;
     RECT  18.615 26.293 20.034 32.881 ;
     RECT  18.615 32.881 20.754 32.999 ;
     RECT  13.032 32.881 13.497 33.035 ;
     RECT  18.615 32.999 20.286 33.269 ;
     RECT  18.615 33.269 20.106 33.539 ;
     RECT  0.108 35.611 0.126 35.741 ;
     RECT  2.304 32.495 6.534 37.355 ;
     RECT  2.34 37.355 6.534 37.435 ;
     RECT  7.344 31.649 8.097 37.435 ;
     RECT  2.34 37.435 8.097 37.949 ;
     RECT  2.34 37.949 6.534 38.203 ;
     RECT  2.304 38.203 6.534 38.435 ;
     RECT  2.34 38.435 6.534 38.543 ;
     RECT  4.86 38.543 6.534 38.821 ;
     RECT  7.344 37.949 8.097 38.821 ;
     RECT  13.215 33.035 13.497 38.911 ;
     RECT  18.615 33.539 20.034 38.947 ;
     RECT  4.86 38.821 8.097 39.055 ;
     RECT  12.672 38.911 13.497 39.055 ;
     RECT  2.34 38.543 4.122 39.083 ;
     RECT  18.108 38.947 20.034 39.091 ;
     RECT  3.672 39.083 4.122 39.289 ;
     RECT  4.86 39.055 8.154 39.289 ;
     RECT  3.672 39.289 8.154 39.325 ;
     RECT  8.964 29.569 8.982 39.325 ;
     RECT  2.34 39.083 2.826 39.355 ;
     RECT  3.672 39.325 8.982 39.515 ;
     RECT  4.932 39.515 8.982 39.749 ;
     RECT  2.304 39.355 2.826 39.883 ;
     RECT  3.672 39.515 4.122 39.883 ;
     RECT  4.932 39.749 8.766 39.893 ;
     RECT  2.304 39.883 4.122 40.055 ;
     RECT  2.415 40.055 4.122 40.289 ;
     RECT  18.108 39.091 20.466 40.405 ;
     RECT  12.564 39.055 13.497 40.567 ;
     RECT  2.415 40.289 3.222 40.595 ;
     RECT  4.932 39.893 8.154 40.699 ;
     RECT  4.86 40.699 8.154 40.711 ;
     RECT  18.108 40.405 20.61 40.711 ;
     RECT  4.392 40.711 8.154 40.829 ;
     RECT  12.564 40.567 14.094 40.829 ;
     RECT  18.108 40.711 20.826 40.829 ;
     RECT  5.796 40.829 8.154 40.901 ;
     RECT  20.448 40.829 20.826 40.901 ;
     RECT  0.108 40.795 0.126 40.925 ;
     RECT  2.415 40.595 3.006 41.135 ;
     RECT  2.415 41.135 2.697 41.227 ;
     RECT  4.392 40.829 4.95 41.251 ;
     RECT  6.804 40.901 8.154 41.369 ;
     RECT  2.304 41.227 2.697 41.405 ;
     RECT  3.888 41.251 4.95 41.405 ;
     RECT  6.804 41.369 8.097 41.549 ;
     RECT  5.868 40.901 6.066 41.639 ;
     RECT  4.572 41.405 4.95 41.675 ;
     RECT  7.704 41.549 8.097 41.675 ;
     RECT  20.448 40.901 20.61 41.683 ;
     RECT  9.324 41.611 9.342 41.749 ;
     RECT  9.108 41.749 9.342 41.783 ;
     RECT  9.108 41.783 9.126 41.789 ;
     RECT  7.812 41.675 8.097 41.819 ;
     RECT  12.564 40.829 13.497 41.819 ;
     RECT  4.932 41.675 4.95 41.881 ;
     RECT  20.448 41.683 21.186 41.909 ;
     RECT  10.08 41.791 10.098 42.017 ;
     RECT  18.108 40.829 19.71 42.061 ;
     RECT  20.448 41.909 20.718 42.061 ;
     RECT  4.932 41.881 5.346 42.089 ;
     RECT  15.876 42.043 15.894 42.173 ;
     RECT  14.328 41.707 14.346 42.179 ;
     RECT  18.108 42.061 20.718 42.215 ;
     RECT  5.328 42.089 5.346 42.449 ;
     RECT  12.6 41.819 13.497 42.485 ;
     RECT  10.836 42.421 10.854 42.557 ;
     RECT  18.108 42.215 20.61 44.149 ;
     RECT  29.415 2.413 29.697 45.391 ;
     RECT  29.232 45.391 29.697 45.437 ;
     RECT  29.34 45.437 29.697 46.157 ;
     RECT  5.04 46.171 5.058 46.499 ;
     RECT  17.604 44.149 20.61 46.651 ;
     RECT  17.172 46.651 20.61 46.813 ;
     RECT  17.136 46.813 20.61 46.921 ;
     RECT  4.932 46.651 4.95 47.075 ;
     RECT  25.596 46.747 25.614 47.119 ;
     RECT  21.456 46.849 21.474 47.131 ;
     RECT  14.832 47.047 14.85 47.147 ;
     RECT  34.815 2.413 35.097 47.191 ;
     RECT  17.136 46.921 20.646 47.281 ;
     RECT  25.524 47.119 25.614 47.281 ;
     RECT  25.524 47.281 25.65 47.323 ;
     RECT  27.036 46.921 27.054 47.323 ;
     RECT  28.404 47.155 28.422 47.353 ;
     RECT  29.415 46.157 29.697 47.353 ;
     RECT  32.904 47.011 32.922 47.389 ;
     RECT  34.815 47.191 35.442 47.389 ;
     RECT  26.784 47.323 27.054 47.425 ;
     RECT  21.456 47.131 22.05 47.461 ;
     RECT  22.86 47.011 22.878 47.461 ;
     RECT  28.116 47.353 29.697 47.461 ;
     RECT  21.456 47.461 22.878 47.551 ;
     RECT  28.044 47.461 29.697 47.579 ;
     RECT  31.788 47.461 31.806 47.587 ;
     RECT  32.652 47.389 32.922 47.587 ;
     RECT  34.74 47.389 35.442 47.587 ;
     RECT  34.74 47.587 35.73 47.623 ;
     RECT  36.936 47.461 36.954 47.623 ;
     RECT  17.1 47.281 20.646 47.695 ;
     RECT  21.384 47.551 22.878 47.695 ;
     RECT  24.015 30.209 24.297 47.695 ;
     RECT  16.272 47.611 16.29 47.731 ;
     RECT  17.028 47.695 22.878 47.731 ;
     RECT  23.76 47.695 24.297 47.731 ;
     RECT  25.524 47.323 25.83 47.731 ;
     RECT  26.784 47.425 27.198 47.731 ;
     RECT  28.044 47.579 28.422 47.731 ;
     RECT  34.128 47.623 36.954 47.731 ;
     RECT  16.272 47.731 25.83 47.821 ;
     RECT  26.748 47.731 27.198 47.821 ;
     RECT  27.972 47.731 28.422 47.821 ;
     RECT  31.788 47.587 32.922 47.821 ;
     RECT  33.876 47.731 36.954 47.885 ;
     RECT  31.716 47.821 32.922 47.965 ;
     RECT  33.876 47.885 36.702 47.965 ;
     RECT  29.376 47.579 29.697 47.995 ;
     RECT  29.376 47.995 30.114 48.091 ;
     RECT  16.272 47.821 28.422 48.119 ;
     RECT  31.608 47.965 36.702 48.119 ;
     RECT  31.608 48.119 36.522 48.173 ;
     RECT  15.264 48.187 15.282 48.199 ;
     RECT  16.272 48.119 28.278 48.199 ;
     RECT  29.376 48.091 30.294 48.271 ;
     RECT  31.608 48.173 32.814 48.271 ;
     RECT  15.264 48.199 28.278 48.389 ;
     RECT  29.376 48.271 32.814 48.389 ;
     RECT  33.84 48.173 36.522 48.389 ;
     RECT  15.264 48.389 26.154 48.397 ;
     RECT  14.292 48.235 14.31 48.425 ;
     RECT  15.12 48.397 26.154 48.433 ;
     RECT  29.376 48.389 32.67 48.659 ;
     RECT  31.068 48.659 32.67 48.731 ;
     RECT  14.436 48.433 26.154 48.929 ;
     RECT  33.84 48.389 35.097 49.045 ;
     RECT  26.928 48.389 28.206 49.199 ;
     RECT  29.415 48.659 30.294 49.199 ;
     RECT  31.716 48.731 32.67 49.199 ;
     RECT  14.436 48.929 14.454 49.235 ;
     RECT  15.444 48.929 26.154 49.351 ;
     RECT  26.928 49.199 28.098 49.351 ;
     RECT  33.732 49.045 35.097 49.351 ;
     RECT  35.892 48.389 36.522 49.351 ;
     RECT  2.415 41.405 2.697 49.427 ;
     RECT  7.815 41.819 8.097 49.427 ;
     RECT  13.215 42.485 13.497 49.427 ;
     RECT  40.215 2.413 40.497 49.427 ;
     RECT  45.615 27.329 45.897 49.427 ;
     RECT  15.444 49.351 28.098 49.469 ;
     RECT  29.415 49.199 30.258 49.469 ;
     RECT  31.716 49.199 32.418 49.469 ;
     RECT  33.408 49.351 36.522 49.477 ;
     RECT  15.588 49.469 27.918 49.505 ;
     RECT  15.768 49.505 27.918 49.517 ;
     RECT  29.415 49.469 30.078 49.517 ;
     RECT  31.716 49.469 32.238 49.517 ;
     RECT  33.408 49.477 36.558 49.517 ;
     RECT  29.415 49.517 29.646 49.549 ;
     RECT  15.768 49.517 27.306 49.577 ;
     RECT  31.068 49.531 31.086 49.577 ;
     RECT  33.228 49.531 33.246 49.577 ;
     RECT  34.815 49.517 35.406 49.577 ;
     RECT  2.415 49.427 2.505 49.697 ;
     RECT  7.815 49.427 7.905 49.697 ;
     RECT  13.215 49.427 13.305 49.697 ;
     RECT  23.832 49.577 24.105 49.697 ;
     RECT  34.815 49.577 34.905 49.697 ;
     RECT  40.215 49.427 40.305 49.697 ;
     RECT  45.615 49.427 45.705 49.697 ;
     RECT  18.216 49.577 18.774 49.805 ;
     RECT  28.908 49.549 29.646 49.805 ;
     RECT  26.748 49.577 27.306 50.189 ;
     RECT  16.488 49.577 16.506 50.765 ;
     RECT  18.216 49.805 18.234 50.765 ;
     RECT  22.104 49.577 22.122 50.765 ;
     RECT  23.832 49.697 23.85 50.765 ;
     RECT  26.748 50.189 26.766 50.765 ;
     RECT  28.908 49.805 28.926 50.765 ;
    LAYER M4 ;
     RECT  0.06 10.56 2.408 41.256 ;
     RECT  2.408 2.148 2.512 49.692 ;
     RECT  2.512 2.418 2.704 49.422 ;
     RECT  2.704 14.208 2.765 35.976 ;
     RECT  2.704 10.512 2.917 12.744 ;
     RECT  2.704 37.008 2.953 37.656 ;
     RECT  2.704 38.64 3.017 40.92 ;
     RECT  2.765 14.208 3.061 32.232 ;
     RECT  2.953 37.584 3.161 37.656 ;
     RECT  3.017 38.64 3.233 40.392 ;
     RECT  3.233 38.64 3.305 39.912 ;
     RECT  2.917 10.512 3.347 12.264 ;
     RECT  3.061 14.304 3.347 32.232 ;
     RECT  3.305 38.64 3.347 39.096 ;
     RECT  3.347 11.376 3.449 12.264 ;
     RECT  3.347 14.4 3.449 32.232 ;
     RECT  3.161 37.584 3.629 37.608 ;
     RECT  2.765 33.552 3.665 35.976 ;
     RECT  3.665 34.704 3.701 35.976 ;
     RECT  3.665 33.552 3.769 33.672 ;
     RECT  3.769 33.024 3.779 33.672 ;
     RECT  3.449 11.424 3.923 12.264 ;
     RECT  3.449 14.4 3.971 32.04 ;
     RECT  3.971 16.272 3.989 32.04 ;
     RECT  3.701 34.704 4.025 35.352 ;
     RECT  3.989 16.272 4.032 16.584 ;
     RECT  3.923 11.424 4.097 11.448 ;
     RECT  3.971 14.4 4.115 15 ;
     RECT  3.989 17.952 4.169 32.04 ;
     RECT  4.025 34.752 4.169 35.352 ;
     RECT  4.032 16.272 4.205 16.536 ;
     RECT  4.169 18 4.307 32.04 ;
     RECT  4.307 19.968 4.457 32.04 ;
     RECT  4.457 23.184 4.547 26.232 ;
     RECT  4.457 27.936 4.565 30.648 ;
     RECT  4.205 16.32 4.601 16.536 ;
     RECT  4.549 14.016 4.637 14.04 ;
     RECT  4.457 19.968 4.643 21.432 ;
     RECT  4.547 23.184 4.673 26.04 ;
     RECT  4.307 18 4.709 18.984 ;
     RECT  4.565 28.176 4.739 30.648 ;
     RECT  4.643 19.968 4.817 21.144 ;
     RECT  3.779 33.024 4.835 33.048 ;
     RECT  4.817 20.016 4.889 21.144 ;
     RECT  3.347 38.64 4.931 38.664 ;
     RECT  4.673 23.232 4.972 26.04 ;
     RECT  4.709 18.96 4.997 18.984 ;
     RECT  4.739 30.624 5.069 30.648 ;
     RECT  4.693 46.176 5.069 46.2 ;
     RECT  4.889 20.496 5.075 21.144 ;
     RECT  4.972 24.432 5.075 26.04 ;
     RECT  4.972 23.232 5.177 23.448 ;
     RECT  4.457 32.016 5.177 32.04 ;
     RECT  4.601 16.512 5.321 16.536 ;
     RECT  5.075 24.528 5.393 26.04 ;
     RECT  4.169 34.752 5.605 34.776 ;
     RECT  4.739 28.176 5.699 29.016 ;
     RECT  5.605 34.752 5.699 35.352 ;
     RECT  5.699 28.224 5.795 28.92 ;
     RECT  4.849 40.704 5.857 40.728 ;
     RECT  5.795 28.224 5.933 28.488 ;
     RECT  5.933 28.224 6.041 28.296 ;
     RECT  5.857 40.704 6.044 41.256 ;
     RECT  6.044 40.176 6.073 41.256 ;
     RECT  6.073 39.6 6.131 41.256 ;
     RECT  6.131 41.232 6.853 41.256 ;
     RECT  5.075 20.592 6.956 21.144 ;
     RECT  4.885 37.584 6.956 37.608 ;
     RECT  6.956 20.592 7.808 21.24 ;
     RECT  5.177 23.424 7.808 23.448 ;
     RECT  5.393 25.824 7.808 26.04 ;
     RECT  6.041 28.224 7.808 28.248 ;
     RECT  7.333 33.12 7.808 33.144 ;
     RECT  5.699 34.752 7.808 34.776 ;
     RECT  6.956 37.584 7.808 37.944 ;
     RECT  6.131 39.6 7.808 39.624 ;
     RECT  6.853 41.232 7.808 41.928 ;
     RECT  7.808 2.148 7.912 49.692 ;
     RECT  7.912 2.418 8.104 49.422 ;
     RECT  8.104 41.76 9.313 41.928 ;
     RECT  8.104 23.424 9.733 23.448 ;
     RECT  8.104 25.824 9.785 26.04 ;
     RECT  9.785 25.824 9.813 25.896 ;
     RECT  9.313 41.616 10.109 41.928 ;
     RECT  9.733 23.424 10.865 23.88 ;
     RECT  9.813 25.872 11.363 25.896 ;
     RECT  10.109 41.616 13.093 41.64 ;
     RECT  10.865 23.568 13.208 23.88 ;
     RECT  11.317 27.12 13.208 27.144 ;
     RECT  8.104 33.12 13.208 33.144 ;
     RECT  13.093 41.616 13.208 41.736 ;
     RECT  13.208 2.148 13.312 49.692 ;
     RECT  13.312 2.418 13.504 49.422 ;
     RECT  13.504 41.712 14.357 42.168 ;
     RECT  13.504 23.568 14.821 23.88 ;
     RECT  14.821 23.568 14.867 23.976 ;
     RECT  14.867 23.856 14.969 23.976 ;
     RECT  15.253 48.192 15.692 48.216 ;
     RECT  14.357 41.904 15.905 42.168 ;
     RECT  15.692 48.192 16.045 49.032 ;
     RECT  16.045 48.192 16.22 49.56 ;
     RECT  16.22 47.616 16.307 49.56 ;
     RECT  16.477 50.736 16.643 50.76 ;
     RECT  16.307 48.912 16.805 49.56 ;
     RECT  17.377 46.704 18.061 46.728 ;
     RECT  18.061 46.608 18.325 46.728 ;
     RECT  18.205 50.736 18.371 50.76 ;
     RECT  18.325 46.608 18.38 46.824 ;
     RECT  18.38 46.368 18.421 46.824 ;
     RECT  14.969 23.856 18.469 23.88 ;
     RECT  13.504 27.12 18.469 27.144 ;
     RECT  15.905 41.904 18.601 42.072 ;
     RECT  18.469 23.856 18.608 25.176 ;
     RECT  18.469 26.208 18.608 27.144 ;
     RECT  15.301 30.096 18.608 30.12 ;
     RECT  13.504 33.12 18.608 33.144 ;
     RECT  18.601 41.904 18.608 42.504 ;
     RECT  18.421 46.368 18.608 47.16 ;
     RECT  18.025 48.144 18.608 48.168 ;
     RECT  16.805 49.536 18.608 49.56 ;
     RECT  18.608 2.148 18.712 49.692 ;
     RECT  18.712 2.418 18.716 49.692 ;
     RECT  18.716 2.418 18.803 49.8 ;
     RECT  18.803 2.418 18.904 49.56 ;
     RECT  18.904 41.952 19.427 42.504 ;
     RECT  18.904 46.176 19.468 47.16 ;
     RECT  18.904 33.12 19.505 33.144 ;
     RECT  19.427 41.952 19.577 41.976 ;
     RECT  19.468 47.136 20.185 47.16 ;
     RECT  20.185 47.136 20.533 47.88 ;
     RECT  18.904 48.864 20.533 49.56 ;
     RECT  20.533 47.136 20.579 49.56 ;
     RECT  20.579 47.136 21.449 48.408 ;
     RECT  22.093 50.736 22.259 50.76 ;
     RECT  21.449 47.136 22.741 47.16 ;
     RECT  21.449 48.384 22.741 48.408 ;
     RECT  22.741 47.136 22.745 48.408 ;
     RECT  22.745 47.136 22.889 48.072 ;
     RECT  23.821 50.736 23.987 50.76 ;
     RECT  18.904 23.856 24.008 24.216 ;
     RECT  18.904 27.12 24.008 27.144 ;
     RECT  18.904 30.096 24.008 30.12 ;
     RECT  22.889 47.136 24.008 47.976 ;
     RECT  20.579 49.536 24.008 49.56 ;
     RECT  24.008 2.148 24.112 49.692 ;
     RECT  24.112 2.418 24.304 49.56 ;
     RECT  24.304 47.136 24.545 47.976 ;
     RECT  24.304 30.096 24.797 30.12 ;
     RECT  24.545 47.136 25.585 47.88 ;
     RECT  25.585 46.752 25.841 47.88 ;
     RECT  24.304 23.856 25.955 24.216 ;
     RECT  25.868 30 25.955 30.024 ;
     RECT  25.841 46.752 25.955 47.352 ;
     RECT  24.304 49.536 26.579 49.56 ;
     RECT  26.737 50.736 27.011 50.76 ;
     RECT  25.955 47.328 27.065 47.352 ;
     RECT  27.277 50.16 27.443 50.184 ;
     RECT  27.829 49.488 27.929 49.512 ;
     RECT  28.897 50.736 29.171 50.76 ;
     RECT  25.909 45.408 29.269 45.432 ;
     RECT  25.955 24.192 29.408 24.216 ;
     RECT  24.304 27.12 29.408 27.144 ;
     RECT  29.269 45.408 29.408 46.152 ;
     RECT  27.961 47.856 29.408 47.88 ;
     RECT  29.408 2.148 29.512 49.692 ;
     RECT  29.512 2.418 29.557 49.692 ;
     RECT  29.557 2.418 29.657 49.8 ;
     RECT  29.657 2.418 29.704 49.512 ;
     RECT  29.704 49.488 30.089 49.512 ;
     RECT  31.057 49.536 31.331 49.56 ;
     RECT  29.704 48 31.637 48.024 ;
     RECT  31.717 49.488 32.249 49.512 ;
     RECT  33.217 49.536 33.491 49.56 ;
     RECT  32.245 48.144 34.333 48.168 ;
     RECT  29.704 24.192 34.808 24.216 ;
     RECT  29.704 27.12 34.808 27.144 ;
     RECT  34.333 47.952 34.808 48.168 ;
     RECT  33.877 49.488 34.808 49.512 ;
     RECT  34.808 2.148 34.912 49.692 ;
     RECT  34.912 2.418 35.104 49.56 ;
     RECT  35.104 49.488 35.651 49.56 ;
     RECT  35.104 47.952 35.741 47.976 ;
     RECT  35.651 49.488 36.569 49.512 ;
     RECT  35.104 24.192 40.208 24.216 ;
     RECT  35.104 27.12 40.208 27.144 ;
     RECT  40.208 2.148 40.312 49.692 ;
     RECT  40.312 2.418 40.504 49.422 ;
     RECT  40.504 27.12 42.181 27.144 ;
     RECT  40.504 24.192 42.227 24.216 ;
     RECT  42.181 25.632 42.401 27.144 ;
     RECT  42.401 25.632 45.529 25.656 ;
     RECT  45.529 25.536 45.608 25.656 ;
     RECT  42.401 27.12 45.608 27.144 ;
     RECT  45.608 2.148 45.712 49.692 ;
     RECT  45.712 2.418 45.904 49.422 ;
     RECT  45.904 25.536 47.141 25.56 ;
     RECT  47.141 25.536 47.173 26.232 ;
     RECT  47.173 25.056 47.219 26.232 ;
     RECT  47.219 26.208 47.225 26.232 ;
     RECT  47.219 25.056 47.26 25.08 ;
     RECT  50.641 26.544 50.677 26.568 ;
     RECT  50.677 24.816 51.804 27 ;
    LAYER M5 ;
     RECT  2.4 2.137 2.52 2.151 ;
     RECT  7.8 2.137 7.92 2.151 ;
     RECT  13.2 2.137 13.32 2.151 ;
     RECT  18.6 2.137 18.72 2.151 ;
     RECT  24 2.137 24.12 2.151 ;
     RECT  29.4 2.137 29.52 2.151 ;
     RECT  34.8 2.137 34.92 2.151 ;
     RECT  40.2 2.137 40.32 2.151 ;
     RECT  45.6 2.137 45.72 2.151 ;
     RECT  2.4 2.151 2.712 10.501 ;
     RECT  2.4 10.501 3.336 11.413 ;
     RECT  2.4 11.413 3.912 12.275 ;
     RECT  0.144 13.045 0.168 13.619 ;
     RECT  2.4 12.275 3.336 14.389 ;
     RECT  4.56 14.005 4.584 14.389 ;
     RECT  2.4 14.389 4.584 16.261 ;
     RECT  2.304 16.261 4.584 17.171 ;
     RECT  2.4 17.171 4.584 20.389 ;
     RECT  0.144 19.621 0.168 20.485 ;
     RECT  2.4 20.389 4.632 20.485 ;
     RECT  0.144 20.485 0.216 20.627 ;
     RECT  2.4 20.485 5.064 20.677 ;
     RECT  7.8 2.151 8.112 21.205 ;
     RECT  2.304 20.677 5.064 21.971 ;
     RECT  0.144 20.627 0.168 22.259 ;
     RECT  14.832 23.557 14.856 23.987 ;
     RECT  18.6 2.151 18.912 24.181 ;
     RECT  2.4 21.971 5.064 24.517 ;
     RECT  2.4 24.517 5.112 24.659 ;
     RECT  0.144 24.805 0.168 25.139 ;
     RECT  7.008 21.205 8.112 25.859 ;
     RECT  9.744 23.845 9.768 25.859 ;
     RECT  18.48 24.181 18.912 26.243 ;
     RECT  47.184 25.045 47.208 26.243 ;
     RECT  42.192 24.181 42.216 26.291 ;
     RECT  2.4 24.659 4.824 26.389 ;
     RECT  11.328 25.861 11.352 27.155 ;
     RECT  2.304 26.389 4.824 28.165 ;
     RECT  2.304 28.165 5.688 28.213 ;
     RECT  2.304 28.213 5.784 28.787 ;
     RECT  2.4 28.787 5.784 28.931 ;
     RECT  2.4 28.931 5.688 30.659 ;
     RECT  2.4 30.659 3.816 30.803 ;
     RECT  0.144 28.453 0.168 30.899 ;
     RECT  2.4 30.803 3.768 33.013 ;
     RECT  4.8 30.659 5.688 33.013 ;
     RECT  7.8 25.859 8.112 33.109 ;
     RECT  2.4 33.013 5.688 33.683 ;
     RECT  0.144 33.877 0.168 34.165 ;
     RECT  0.144 34.165 0.264 34.355 ;
     RECT  2.4 33.683 3.672 34.835 ;
     RECT  0.144 34.355 0.168 35.363 ;
     RECT  4.704 33.683 5.688 35.363 ;
     RECT  2.4 34.835 3.432 35.939 ;
     RECT  2.4 35.939 3.336 35.987 ;
     RECT  2.4 35.987 2.712 36.997 ;
     RECT  4.704 35.363 4.728 37.573 ;
     RECT  2.4 36.997 2.904 37.667 ;
     RECT  7.344 33.109 8.112 37.909 ;
     RECT  2.4 37.667 2.712 38.629 ;
     RECT  4.704 37.573 4.92 38.675 ;
     RECT  2.4 38.629 3.336 39.107 ;
     RECT  0.144 36.901 0.168 39.395 ;
     RECT  2.4 39.107 3.144 39.923 ;
     RECT  7.008 37.909 8.112 40.165 ;
     RECT  6.096 40.165 8.112 41.267 ;
     RECT  13.2 2.151 13.512 41.605 ;
     RECT  13.104 41.605 13.512 41.747 ;
     RECT  18.6 26.243 18.912 41.893 ;
     RECT  6.864 41.267 8.112 41.939 ;
     RECT  18.432 41.893 18.912 41.941 ;
     RECT  15.312 30.085 15.336 42.037 ;
     RECT  29.4 2.151 29.712 46.117 ;
     RECT  4.704 38.675 4.728 46.211 ;
     RECT  18.432 41.941 19.416 46.739 ;
     RECT  25.92 23.845 25.944 46.787 ;
     RECT  18.432 46.739 18.912 46.789 ;
     RECT  24 2.151 24.312 47.557 ;
     RECT  23.376 47.557 24.312 47.699 ;
     RECT  29.28 46.117 29.712 47.891 ;
     RECT  18.336 46.789 18.912 48.179 ;
     RECT  29.4 47.891 29.712 49.477 ;
     RECT  34.8 2.151 35.112 49.477 ;
     RECT  15.312 42.037 16.296 49.525 ;
     RECT  18.6 48.179 18.912 49.525 ;
     RECT  20.544 47.845 20.568 49.525 ;
     RECT  24 47.699 24.312 49.525 ;
     RECT  31.728 49.477 32.184 49.525 ;
     RECT  33.888 49.477 36.504 49.525 ;
     RECT  2.4 39.923 2.712 49.689 ;
     RECT  7.8 41.939 8.112 49.689 ;
     RECT  13.2 41.747 13.512 49.689 ;
     RECT  40.2 2.151 40.512 49.689 ;
     RECT  45.6 2.151 45.912 49.689 ;
     RECT  2.4 49.689 2.52 49.703 ;
     RECT  7.8 49.689 7.92 49.703 ;
     RECT  13.2 49.689 13.32 49.703 ;
     RECT  29.4 49.477 30.024 49.703 ;
     RECT  33.456 49.525 36.504 49.703 ;
     RECT  40.2 49.689 40.32 49.703 ;
     RECT  45.6 49.689 45.72 49.703 ;
     RECT  15.312 49.525 26.568 50.149 ;
     RECT  27.84 49.477 27.864 50.149 ;
     RECT  29.568 49.703 30.024 50.725 ;
     RECT  15.312 50.149 27.864 51.792 ;
     RECT  29.136 50.725 30.024 51.792 ;
     RECT  31.296 49.525 32.184 51.792 ;
     RECT  33.456 49.703 34.344 51.792 ;
     RECT  35.616 49.703 36.504 51.792 ;
     RECT  3.336 14.005 4.56 14.389 ;
     RECT  13.512 23.557 14.832 23.987 ;
     RECT  45.912 25.045 47.184 26.243 ;
     RECT  3.816 30.659 4.8 30.803 ;
     RECT  3.768 30.803 4.8 33.013 ;
     RECT  3.672 33.683 4.704 34.835 ;
     RECT  3.432 34.835 4.704 35.939 ;
     RECT  3.336 35.939 4.704 35.987 ;
     RECT  2.712 35.987 2.904 36.997 ;
     RECT  2.712 37.667 2.904 38.629 ;
     RECT  3.336 38.629 4.704 39.107 ;
     RECT  4.728 38.675 4.92 40.165 ;
     RECT  4.728 40.165 6.096 41.267 ;
     RECT  18.336 48.179 18.6 49.525 ;
     RECT  26.568 49.525 27.84 50.149 ;
     RECT  30.024 49.525 31.296 51.708 ;
     RECT  32.184 49.525 33.456 51.708 ;
     RECT  29.4 49.703 29.568 50.725 ;
     RECT  34.344 49.703 35.616 51.708 ;
     RECT  27.864 50.725 29.136 51.708 ;
     RECT  27.912 51.708 28.224 51.792 ;
     RECT  28.344 51.708 28.656 51.792 ;
     RECT  28.776 51.708 29.088 51.792 ;
     RECT  30.072 51.708 30.384 51.792 ;
     RECT  30.504 51.708 30.816 51.792 ;
     RECT  30.936 51.708 31.248 51.792 ;
     RECT  32.232 51.708 32.544 51.792 ;
     RECT  32.664 51.708 32.976 51.792 ;
     RECT  33.096 51.708 33.408 51.792 ;
     RECT  34.392 51.708 34.704 51.792 ;
     RECT  34.824 51.708 35.136 51.792 ;
     RECT  35.256 51.708 35.568 51.792 ;
  END
END dsfd_vm_static_read_v5_p
END LIBRARY
